VERSION 5.8 ;
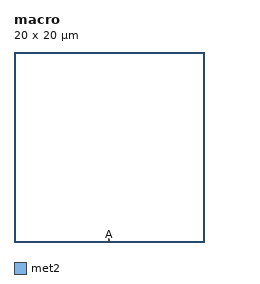
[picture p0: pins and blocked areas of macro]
MACRO macro
  CLASS BLOCK ;
  ORIGIN 0 0 ;
  SIZE 20 BY 20 ;
  PIN A
    DIRECTION INPUT ;
    USE SIGNAL ;
    PORT
      LAYER met2 ;
        RECT 9.93 0 10.07 0.5 ;
    END
  END A
END macro
END LIBRARY
